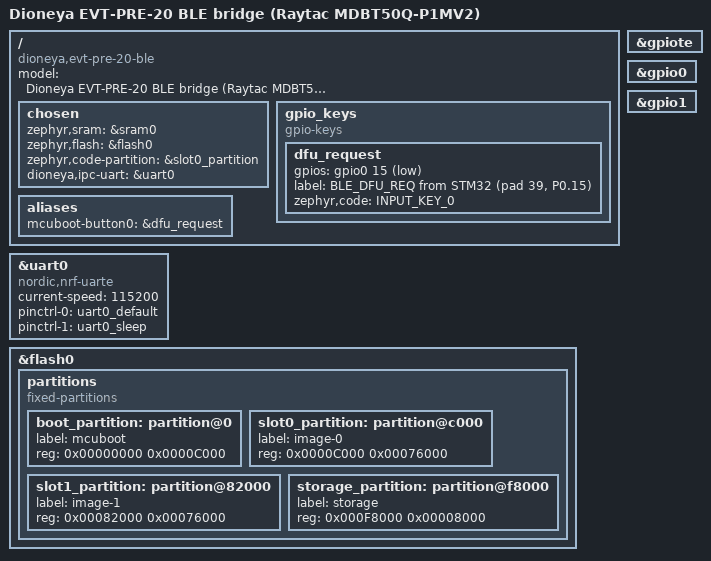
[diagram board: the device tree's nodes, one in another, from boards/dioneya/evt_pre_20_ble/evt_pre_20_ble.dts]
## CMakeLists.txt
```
# Dioneya nRF52840 BLE bridge — Zephyr / nRF Connect SDK application.
# NOT built by the repository CI (no NCS there): build with west on a machine with NCS v2.7+:
#   west build -b evt_pre_20_ble          firmware/targets/nrf52840_ble   # Rev.A carrier, U11 Raytac MDBT50Q-P1MV2
#   west build -b nrf52840dk/nrf52840     firmware/targets/nrf52840_ble   # bench on the DK (uart1 P1.01/P1.02 overlay)
# The bridge logic itself (zs_ble_bridge, zs_ipc_link, zs_ble_framing) is host-tested in firmware/tests.
cmake_minimum_required(VERSION 3.20.0)
list(APPEND BOARD_ROOT ${CMAKE_CURRENT_SOURCE_DIR})   # boards/dioneya/evt_pre_20_ble
find_package(Zephyr REQUIRED HINTS $ENV{ZEPHYR_BASE})
project(dioneya_nrf52840_ble)

set(ZS_FW_ROOT ${CMAKE_CURRENT_SOURCE_DIR}/../..)
target_sources(app PRIVATE
  src/main.c
  src/gatt.c
  src/ipc_uart.c
  ${ZS_FW_ROOT}/src/zs_ble_framing.c
  ${ZS_FW_ROOT}/src/zs_ipc_link.c
  ${ZS_FW_ROOT}/src/zs_ble_bridge.c
  ${ZS_FW_ROOT}/src/zs_sha256.c
)
target_include_directories(app PRIVATE ${ZS_FW_ROOT}/include src)
```

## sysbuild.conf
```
# NCS sysbuild: MCUboot in front of the bridge application (flash map: boards/dioneya/evt_pre_20_ble + pm_static.yml).
# The signing key is the pilot key from the PKI: muhoed-pki nrf-boot-key  ->  <pki>/nrf-boot/nrf-boot.key.pem
#   west build -b evt_pre_20_ble firmware/targets/nrf52840_ble -- -DSB_CONFIG_BOOT_SIGNATURE_KEY_FILE=\"/abs/path/nrf-boot.key.pem\"
SB_CONFIG_BOOTLOADER_MCUBOOT=y
SB_CONFIG_BOOT_SIGNATURE_TYPE_ECDSA_P256=y
# NCS 2.7 / MCUboot uses the move-based, no-scratch swap under this
# Kconfig name.  The two 472 KiB slots in pm_static.yml are equal-sized.
SB_CONFIG_MCUBOOT_MODE_SWAP_WITHOUT_SCRATCH=y
```

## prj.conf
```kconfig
# Dioneya nRF52840 BLE bridge (ICD addendum B + C)
CONFIG_BT=y
CONFIG_BT_PERIPHERAL=y
CONFIG_BT_CTLR=y
CONFIG_BT_DEVICE_NAME="DIO-EVT-000"
CONFIG_BT_DEVICE_NAME_DYNAMIC=y
CONFIG_BT_DEVICE_NAME_MAX=31
CONFIG_BT_MAX_CONN=1
CONFIG_BT_SMP=y
CONFIG_BT_SMP_SC_PAIR_ONLY=y
CONFIG_BT_FIXED_PASSKEY=y
CONFIG_BT_BONDABLE=n
CONFIG_BT_GATT_DYNAMIC_DB=n
CONFIG_BT_GATT_CLIENT=n
# ATT MTU 247 (addendum B.2): ACL 251-byte buffers on both directions
CONFIG_BT_L2CAP_TX_MTU=247
CONFIG_BT_BUF_ACL_RX_SIZE=251
CONFIG_BT_BUF_ACL_TX_SIZE=251
CONFIG_BT_DATA_LEN_UPDATE=y
CONFIG_BT_CTLR_DATA_LENGTH_MAX=251
# The installer (GATT client) initiates ATT MTU exchange.  A peripheral-only
# bridge must not enable BT_GATT_AUTO_UPDATE_MTU, which depends on GATT client.
# Application diagnostics use RTT and never consume the STM32 IPC UART.
CONFIG_USE_SEGGER_RTT=y
CONFIG_RTT_CONSOLE=y
CONFIG_CONSOLE=y
# UART link to the STM32U585 (uart1, interrupt driven)
CONFIG_SERIAL=y
CONFIG_UART_INTERRUPT_DRIVEN=y
CONFIG_RING_BUFFER=y
CONFIG_MAIN_STACK_SIZE=4096
CONFIG_SYSTEM_WORKQUEUE_STACK_SIZE=4096
CONFIG_LOG=y
CONFIG_LOG_DEFAULT_LEVEL=3
CONFIG_ASSERT=y
# MCUboot image management: the bridge confirms itself once the STM32 link is proven (addendum C.6).
CONFIG_FLASH=y
CONFIG_FLASH_MAP=y
CONFIG_STREAM_FLASH=y
CONFIG_IMG_MANAGER=y
CONFIG_MCUBOOT_IMG_MANAGER=y
CONFIG_MCUBOOT_IMGTOOL_SIGN_VERSION="0.1.0+2026101601"
```

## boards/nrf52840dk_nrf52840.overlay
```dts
/* Bring-up on the nRF52840 DK: uart1 on P1.01 (TX) / P1.02 (RX) toward the STM32U585 USART3 (PB10 TX / PB11 RX).
   The Rev.A station carrier assigns the module pins in the board contract; add an overlay per board there. */
&pinctrl {
	uart1_default: uart1_default {
		group1 { psels = <NRF_PSEL(UART_TX, 1, 1)>; };
		group2 { psels = <NRF_PSEL(UART_RX, 1, 2)>; bias-pull-up; };
	};
	uart1_sleep: uart1_sleep {
		group1 { psels = <NRF_PSEL(UART_TX, 1, 1)>, <NRF_PSEL(UART_RX, 1, 2)>; low-power-enable; };
	};
};

&uart1 {
	status = "okay";
	current-speed = <115200>;
	pinctrl-0 = <&uart1_default>;
	pinctrl-1 = <&uart1_sleep>;
	pinctrl-names = "default", "sleep";
};

/ {
	chosen {
		dioneya,ipc-uart = &uart1;
	};
};
```

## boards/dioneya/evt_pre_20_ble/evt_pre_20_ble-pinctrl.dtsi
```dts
/* U11 pad 22 P0.06 = UARTE TX (BLE_RX net), pad 24 P0.08 = UARTE RX (BLE_TX net); no RTS/CTS on Rev.A. */
&pinctrl {
	uart0_default: uart0_default {
		group1 {
			psels = <NRF_PSEL(UART_TX, 0, 6)>;
		};
		group2 {
			psels = <NRF_PSEL(UART_RX, 0, 8)>;
			bias-pull-up;
		};
	};

	uart0_sleep: uart0_sleep {
		group1 {
			psels = <NRF_PSEL(UART_TX, 0, 6)>,
				<NRF_PSEL(UART_RX, 0, 8)>;
			low-power-enable;
		};
	};
};
```

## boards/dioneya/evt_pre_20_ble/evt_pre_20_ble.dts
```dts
/*
 * Dioneya EVT-PRE-20 Rev.A, BLE bridge: Raytac MDBT50Q-P1MV2 (nRF52840 QIAA) = U11 on PCB-MAIN.
 * Wiring from hardware/PCB_MAIN_BLE_PIN_AUTHORITY_REV_A.csv (authority: Raytac Ver.L + Rev.A netlist):
 *   pad 22 P0.06  nRF UARTE TX  -> STM32 PB11 USART3_RX   (net BLE_RX, 22 R series at U11)
 *   pad 24 P0.08  nRF UARTE RX  <- STM32 PB10 USART3_TX   (net BLE_TX, 22 R series at STM32)
 *   pad 39 P0.15  BLE_DFU_REQ   <- STM32 PB2 open-drain, 10 k pull-up, active LOW, sampled by the bootloader at reset release
 *   pad 40 P0.18/nRESET         <- reset buffer from STM32 BLE_EN (LOW = held in reset), 10 k pull-up
 *   VDD = VDDH = 3V3_DIGITAL (normal-voltage mode, Reg0 DC/DC unused), no 32.768 kHz crystal, no NFC, no USB, no flow control.
 *   SWDIO/SWDCLK -> TP_BLE_SWD fixture pads (separate from the STM32 SWD).
 */
/dts-v1/;
#include <nordic/nrf52840_qiaa.dtsi>
#include <zephyr/dt-bindings/input/input-event-codes.h>
#include "evt_pre_20_ble-pinctrl.dtsi"

/ {
	model = "Dioneya EVT-PRE-20 BLE bridge (Raytac MDBT50Q-P1MV2)";
	compatible = "dioneya,evt-pre-20-ble";

	chosen {
		zephyr,sram = &sram0;
		zephyr,flash = &flash0;
		zephyr,code-partition = &slot0_partition;
		dioneya,ipc-uart = &uart0;
	};

	gpio_keys {
		compatible = "gpio-keys";
		dfu_request: dfu_request {
			gpios = <&gpio0 15 GPIO_ACTIVE_LOW>;
			label = "BLE_DFU_REQ from STM32 (pad 39, P0.15)";
			zephyr,code = <INPUT_KEY_0>;
		};
	};

	aliases {
		mcuboot-button0 = &dfu_request;
	};
};

&gpiote {
	status = "okay";
};

&gpio0 {
	status = "okay";
};

&gpio1 {
	status = "okay";
};

&uart0 {
	compatible = "nordic,nrf-uarte";
	status = "okay";
	current-speed = <115200>;
	pinctrl-0 = <&uart0_default>;
	pinctrl-1 = <&uart0_sleep>;
	pinctrl-names = "default", "sleep";
};

&flash0 {
	partitions {
		compatible = "fixed-partitions";
		#address-cells = <1>;
		#size-cells = <1>;

		boot_partition: partition@0 {
			label = "mcuboot";
			reg = <0x00000000 0x0000C000>;
		};
		slot0_partition: partition@c000 {
			label = "image-0";
			reg = <0x0000C000 0x00076000>;
		};
		slot1_partition: partition@82000 {
			label = "image-1";
			reg = <0x00082000 0x00076000>;
		};
		storage_partition: partition@f8000 {
			label = "storage";
			reg = <0x000F8000 0x00008000>;
		};
	};
};
```

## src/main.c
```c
/*
 * Dioneya nRF52840 BLE bridge: advertising, connection/security events, pairing passkey derived
 * from the label secret, and the glue between zs_ble_bridge and the Zephyr stack.
 * Pairing (addendum B.7): LE Secure Connections, passkey entry with a fixed 6-digit passkey
 *   passkey = BE32(SHA-256("DIO-PAIR-V1" || secret)[0..3]) mod 1_000_000
 * The phone derives the same number from the scanned label and shows it to the installer.
 */
#include "bridge_app.h"

#include <zephyr/bluetooth/bluetooth.h>
#include <zephyr/bluetooth/conn.h>
#include <zephyr/bluetooth/gap.h>
#include <zephyr/bluetooth/uuid.h>
#include <zephyr/kernel.h>
#include <zephyr/logging/log.h>
#include <string.h>
#ifdef CONFIG_MCUBOOT_IMG_MANAGER
#include <zephyr/dfu/mcuboot.h>
#endif

LOG_MODULE_REGISTER(dio_bridge, LOG_LEVEL_INF);

zs_ble_bridge_t bridge;
static bool window_open;
static struct k_work_delayable window_timer;
static char local_name[32] = CONFIG_BT_DEVICE_NAME;

static const struct bt_data adv_data[] = {
  BT_DATA_BYTES(BT_DATA_FLAGS, BT_LE_AD_GENERAL | BT_LE_AD_NO_BREDR),
  BT_DATA_BYTES(BT_DATA_UUID128_ALL, BT_UUID_128_ENCODE(0xd10e0100u, 0x5a53, 0x4c55, 0xb0a1, 0x000000000000ULL)),
};
static struct bt_data scan_rsp[1];

static void start_advertising(void) {
  scan_rsp[0] = (struct bt_data)BT_DATA(BT_DATA_NAME_COMPLETE, local_name, strlen(local_name));
  const int err = bt_le_adv_start(BT_LE_ADV_CONN, adv_data, ARRAY_SIZE(adv_data), scan_rsp, ARRAY_SIZE(scan_rsp));
  if (err && err != -EALREADY) LOG_ERR("adv start %d", err);
}

static void window_expired(struct k_work *work) {
  ARG_UNUSED(work);
  window_open = false;
  (void)bt_le_adv_stop();
  LOG_INF("service window closed");
}

void app_advertise(bool on, uint16_t seconds) {
  window_open = on;
  if (on) {
    start_advertising();
    if (seconds) k_work_reschedule(&window_timer, K_SECONDS(seconds)); else k_work_cancel_delayable(&window_timer);
  } else {
    k_work_cancel_delayable(&window_timer);
    (void)bt_le_adv_stop();
  }
}

/* A freshly swapped-in image is confirmed only after the STM32 has talked to it (IDENTITY_SET arrives at the
   service init and after every recovery); an image that never hears the STM32 is reverted by MCUboot on the
   next reset, which is how a broken bridge update heals itself (addendum C.6). */
static void confirm_running_image(void) {
#ifdef CONFIG_MCUBOOT_IMG_MANAGER
  if (!boot_is_img_confirmed()) {
    const int err = boot_write_img_confirmed();
    LOG_INF("image confirmed (%d)", err);
  }
#endif
}

void app_set_local_name(const char *name) {
  strncpy(local_name, name, sizeof(local_name) - 1u);
  local_name[sizeof(local_name) - 1u] = '\0';
  (void)bt_set_name(local_name);
  confirm_running_image();
}

void app_set_pairing_secret(const uint8_t secret[16]) {
  (void)bt_passkey_set(zs_ble_pairing_passkey(secret));   /* B.7, host-tested in firmware/tests/test_ble_bridge.c */
  LOG_INF("pairing passkey installed");
}

/* ---- connection and security ------------------------------------------------------------ */

static void connected(struct bt_conn *conn, uint8_t err) {
  if (err) { LOG_WRN("connect failed %u", err); return; }
  gatt_set_conn(bt_conn_ref(conn));
  zs_ble_bridge_on_link(&bridge, 1u);
  LOG_INF("connected");
}

static void disconnected(struct bt_conn *conn, uint8_t reason) {
  LOG_INF("disconnected %u", reason);
  gatt_set_conn(NULL);
  bt_conn_unref(conn);
  zs_ble_bridge_on_link(&bridge, 0u);
  if (window_open) start_advertising();
}

static void security_changed(struct bt_conn *conn, bt_security_t level, enum bt_security_err err) {
  ARG_UNUSED(conn);
  if (err == BT_SECURITY_ERR_SUCCESS && level >= BT_SECURITY_L3) zs_ble_bridge_on_link(&bridge, 2u);   /* authenticated (MITM) LESC */
  LOG_INF("security level %d err %d", level, err);
}

BT_CONN_CB_DEFINE(conn_cb) = {
  .connected = connected,
  .disconnected = disconnected,
  .security_changed = security_changed,
};

static void auth_cancel(struct bt_conn *conn) { ARG_UNUSED(conn); LOG_WRN("pairing cancelled"); }
static void auth_passkey_display(struct bt_conn *conn, unsigned int passkey) { ARG_UNUSED(conn); ARG_UNUSED(passkey); }
static const struct bt_conn_auth_cb auth_cb = {
  .passkey_display = auth_passkey_display,   /* display capability: the phone enters the label-derived passkey */
  .cancel = auth_cancel,
};

/* ---- bridge port ------------------------------------------------------------------------- */

static bool port_uart_send(void *ctx, const uint8_t *wire, size_t len) { ARG_UNUSED(ctx); return ipc_uart_send(wire, len); }
static bool port_notify(void *ctx, uint16_t id, const uint8_t *frame, size_t len) { ARG_UNUSED(ctx); return gatt_notify_frame(id, frame, len); }
static size_t port_att(void *ctx) { ARG_UNUSED(ctx); return gatt_att_payload(); }
static void port_advertise(void *ctx, bool on, uint16_t s) { ARG_UNUSED(ctx); app_advertise(on, s); }
static void port_name(void *ctx, const char *n) { ARG_UNUSED(ctx); app_set_local_name(n); }
static void port_secret(void *ctx, const uint8_t s[16]) { ARG_UNUSED(ctx); app_set_pairing_secret(s); }

static const zs_ble_bridge_port_t port = {NULL, port_uart_send, port_notify, port_att, port_advertise, port_name, port_secret};

int main(void) {
  k_work_init_delayable(&window_timer, window_expired);
  zs_ble_bridge_init(&bridge, &port);
  if (ipc_uart_init()) return -1;
  int err = bt_enable(NULL);
  if (err) { LOG_ERR("bt_enable %d", err); return err; }
  (void)bt_conn_auth_cb_register(&auth_cb);
  (void)gatt_init();
  LOG_INF("Dioneya BLE bridge ready; waiting for the STM32 (IDENTITY_SET / SERVICE_WINDOW)");
  for (;;) ipc_uart_poll();   /* feeds the bridge; every reply goes back over the UART from the same thread */
  return 0;
}
```

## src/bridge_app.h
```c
#ifndef BRIDGE_APP_H
#define BRIDGE_APP_H
/* Glue between the portable zs_ble_bridge core and the Zephyr BLE stack / UART. */
#include "zs_ble_bridge.h"
#include <zephyr/bluetooth/conn.h>

extern zs_ble_bridge_t bridge;

/* gatt.c */
int gatt_init(void);
bool gatt_notify_frame(uint16_t char_id, const uint8_t *frame, size_t len);
size_t gatt_att_payload(void);
void gatt_set_conn(struct bt_conn *conn);

/* ipc_uart.c */
int ipc_uart_init(void);
bool ipc_uart_send(const uint8_t *wire, size_t len);
/* Drains received bytes into the bridge; called from the main loop. */
void ipc_uart_poll(void);

/* main.c */
void app_advertise(bool on, uint16_t seconds);
void app_set_local_name(const char *name);
void app_set_pairing_secret(const uint8_t secret[16]);

#endif
```

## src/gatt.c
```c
/* GATT table of ICD addendum B.1 on top of the portable bridge (zs_ble_bridge). */
#include "bridge_app.h"

#include <zephyr/bluetooth/bluetooth.h>
#include <zephyr/bluetooth/gatt.h>
#include <zephyr/bluetooth/uuid.h>
#include <zephyr/logging/log.h>

LOG_MODULE_REGISTER(gatt, LOG_LEVEL_INF);

/* d10eXXXX-5a53-4c55-b0a1-000000000000 */
#define DIO_UUID(id16) BT_UUID_DECLARE_128(BT_UUID_128_ENCODE(0xd10e0000u | (id16), 0x5a53, 0x4c55, 0xb0a1, 0x000000000000ULL))

static struct bt_conn *current_conn;

static ssize_t read_cb(struct bt_conn *conn, const struct bt_gatt_attr *attr, void *buf, uint16_t len, uint16_t offset) {
  const uint16_t char_id = (uint16_t)(uintptr_t)attr->user_data;
  uint8_t frame[ZS_BLE_ATT_PAYLOAD_MAX];
  size_t n;
  if (offset != 0u) return BT_GATT_ERR(BT_ATT_ERR_INVALID_OFFSET); /* every ATT read is one frame (B.2) */
  if (!zs_ble_bridge_on_gatt_read(&bridge, char_id, frame, sizeof(frame), &n)) return BT_GATT_ERR(BT_ATT_ERR_UNLIKELY);
  return bt_gatt_attr_read(conn, attr, buf, len, 0u, frame, (uint16_t)n);
}

static ssize_t write_cb(struct bt_conn *conn, const struct bt_gatt_attr *attr, const void *buf, uint16_t len, uint16_t offset, uint8_t flags) {
  const uint16_t char_id = (uint16_t)(uintptr_t)attr->user_data;
  ARG_UNUSED(conn); ARG_UNUSED(flags);
  if (offset != 0u) return BT_GATT_ERR(BT_ATT_ERR_INVALID_OFFSET);
  if (!zs_ble_bridge_on_gatt_write(&bridge, char_id, buf, len)) return BT_GATT_ERR(BT_ATT_ERR_VALUE_NOT_ALLOWED);
  return len;
}

static void ccc_changed(const struct bt_gatt_attr *attr, uint16_t value) { ARG_UNUSED(attr); ARG_UNUSED(value); }

#define CHAR_ID(id) ((void *)(uintptr_t)(id))
/* Reads before pairing are allowed only for identity (B.4); everything else needs an authenticated (MITM) link. */
BT_GATT_SERVICE_DEFINE(dio_device_info,
  BT_GATT_PRIMARY_SERVICE(DIO_UUID(0x0100)),
  BT_GATT_CHARACTERISTIC(DIO_UUID(0x0101), BT_GATT_CHRC_READ, BT_GATT_PERM_READ, read_cb, NULL, CHAR_ID(ZS_CHAR_IDENTITY)),
);

BT_GATT_SERVICE_DEFINE(dio_configuration,
  BT_GATT_PRIMARY_SERVICE(DIO_UUID(0x0200)),
  BT_GATT_CHARACTERISTIC(DIO_UUID(0x0201), BT_GATT_CHRC_READ | BT_GATT_CHRC_NOTIFY, BT_GATT_PERM_READ_AUTHEN, read_cb, NULL, CHAR_ID(ZS_CHAR_CONFIG_READ)),
  BT_GATT_CCC(ccc_changed, BT_GATT_PERM_READ | BT_GATT_PERM_WRITE_AUTHEN),
  BT_GATT_CHARACTERISTIC(DIO_UUID(0x0202), BT_GATT_CHRC_WRITE | BT_GATT_CHRC_NOTIFY, BT_GATT_PERM_WRITE_AUTHEN, NULL, write_cb, CHAR_ID(ZS_CHAR_CONFIG_WRITE)),
  BT_GATT_CCC(ccc_changed, BT_GATT_PERM_READ | BT_GATT_PERM_WRITE_AUTHEN),
  BT_GATT_CHARACTERISTIC(DIO_UUID(0x0203), BT_GATT_CHRC_READ | BT_GATT_CHRC_WRITE | BT_GATT_CHRC_NOTIFY, BT_GATT_PERM_READ_AUTHEN | BT_GATT_PERM_WRITE_AUTHEN, read_cb, write_cb, CHAR_ID(ZS_CHAR_INSTALLATION_POSITION)),
  BT_GATT_CCC(ccc_changed, BT_GATT_PERM_READ | BT_GATT_PERM_WRITE_AUTHEN),
  BT_GATT_CHARACTERISTIC(DIO_UUID(0x0204), BT_GATT_CHRC_READ | BT_GATT_CHRC_WRITE | BT_GATT_CHRC_NOTIFY, BT_GATT_PERM_READ_AUTHEN | BT_GATT_PERM_WRITE_AUTHEN, read_cb, write_cb, CHAR_ID(ZS_CHAR_POSITION_TRUST_POLICY)),
  BT_GATT_CCC(ccc_changed, BT_GATT_PERM_READ | BT_GATT_PERM_WRITE_AUTHEN),
  BT_GATT_CHARACTERISTIC(DIO_UUID(0x0205), BT_GATT_CHRC_READ | BT_GATT_CHRC_WRITE | BT_GATT_CHRC_NOTIFY, BT_GATT_PERM_READ_AUTHEN | BT_GATT_PERM_WRITE_AUTHEN, read_cb, write_cb, CHAR_ID(ZS_CHAR_SESSION_ROLE)),   /* B.9 */
  BT_GATT_CCC(ccc_changed, BT_GATT_PERM_READ | BT_GATT_PERM_WRITE_AUTHEN),
  BT_GATT_CHARACTERISTIC(DIO_UUID(0x0206), BT_GATT_CHRC_READ | BT_GATT_CHRC_WRITE | BT_GATT_CHRC_NOTIFY, BT_GATT_PERM_READ_AUTHEN | BT_GATT_PERM_WRITE_AUTHEN, read_cb, write_cb, CHAR_ID(ZS_CHAR_STATION_SECRETS)),   /* v0.3 */
  BT_GATT_CCC(ccc_changed, BT_GATT_PERM_READ | BT_GATT_PERM_WRITE_AUTHEN),
);

BT_GATT_SERVICE_DEFINE(dio_diagnostics,
  BT_GATT_PRIMARY_SERVICE(DIO_UUID(0x0300)),
  BT_GATT_CHARACTERISTIC(DIO_UUID(0x0301), BT_GATT_CHRC_READ | BT_GATT_CHRC_NOTIFY, BT_GATT_PERM_READ_AUTHEN, read_cb, NULL, CHAR_ID(ZS_CHAR_STATUS)),
  BT_GATT_CCC(ccc_changed, BT_GATT_PERM_READ | BT_GATT_PERM_WRITE_AUTHEN),
  BT_GATT_CHARACTERISTIC(DIO_UUID(0x0302), BT_GATT_CHRC_READ | BT_GATT_CHRC_NOTIFY, BT_GATT_PERM_READ_AUTHEN, read_cb, NULL, CHAR_ID(ZS_CHAR_GNSS_INTEGRITY)),
  BT_GATT_CCC(ccc_changed, BT_GATT_PERM_READ | BT_GATT_PERM_WRITE_AUTHEN),
  BT_GATT_CHARACTERISTIC(DIO_UUID(0x0303), BT_GATT_CHRC_WRITE | BT_GATT_CHRC_NOTIFY, BT_GATT_PERM_WRITE_AUTHEN, NULL, write_cb, CHAR_ID(ZS_CHAR_SELF_TEST)),
  BT_GATT_CCC(ccc_changed, BT_GATT_PERM_READ | BT_GATT_PERM_WRITE_AUTHEN),
);

/* Finds the characteristic value attribute for a bridge char id (static tables, so a linear scan is fine). */
static const struct bt_gatt_attr *value_attr(uint16_t char_id) {
  const struct bt_gatt_service_static *svcs[] = {&dio_device_info, &dio_configuration, &dio_diagnostics};
  for (size_t s = 0u; s < ARRAY_SIZE(svcs); s++)
    for (size_t i = 0u; i < svcs[s]->attr_count; i++) {
      const struct bt_gatt_attr *a = &svcs[s]->attrs[i];
      if (a->user_data == CHAR_ID(char_id) && (a->read == read_cb || a->write == write_cb)) return a;
    }
  return NULL;
}

bool gatt_notify_frame(uint16_t char_id, const uint8_t *frame, size_t len) {
  const struct bt_gatt_attr *attr = value_attr(char_id);
  if (attr == NULL || current_conn == NULL) return false;
  if (!bt_gatt_is_subscribed(current_conn, attr, BT_GATT_CCC_NOTIFY)) return false;
  return bt_gatt_notify(current_conn, attr, frame, (uint16_t)len) == 0;
}

size_t gatt_att_payload(void) {
  if (current_conn == NULL) return ZS_BLE_ATT_PAYLOAD_MIN;
  const uint16_t mtu = bt_gatt_get_mtu(current_conn);
  if (mtu < ZS_BLE_ATT_PAYLOAD_MIN + 3u) return ZS_BLE_ATT_PAYLOAD_MIN;
  return mtu - 3u > ZS_BLE_ATT_PAYLOAD_MAX ? ZS_BLE_ATT_PAYLOAD_MAX : mtu - 3u;
}

void gatt_set_conn(struct bt_conn *conn) { current_conn = conn; }

int gatt_init(void) { return 0; }
```

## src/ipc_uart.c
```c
/* Interrupt-driven UART to the STM32U585: RX bytes go to a ring buffer, the main loop feeds the bridge. */
#include "bridge_app.h"

#include <zephyr/device.h>
#include <zephyr/drivers/uart.h>
#include <zephyr/kernel.h>
#include <zephyr/logging/log.h>
#include <zephyr/sys/ring_buffer.h>

LOG_MODULE_REGISTER(ipc_uart, LOG_LEVEL_INF);

static const struct device *const uart_dev = DEVICE_DT_GET(DT_CHOSEN(dioneya_ipc_uart));
RING_BUF_DECLARE(rx_ring, 2048);
static struct k_sem rx_sem;

static void uart_isr(const struct device *dev, void *user_data) {
  uint8_t buf[64];
  ARG_UNUSED(user_data);
  while (uart_irq_update(dev) && uart_irq_is_pending(dev)) {
    if (!uart_irq_rx_ready(dev)) break;
    const int n = uart_fifo_read(dev, buf, sizeof(buf));
    if (n <= 0) break;
    if (ring_buf_put(&rx_ring, buf, (uint32_t)n) != (uint32_t)n) LOG_WRN("rx ring overflow");
    k_sem_give(&rx_sem);
  }
}

int ipc_uart_init(void) {
  if (!device_is_ready(uart_dev)) { LOG_ERR("ipc uart not ready"); return -ENODEV; }
  k_sem_init(&rx_sem, 0, 1);
  uart_irq_callback_user_data_set(uart_dev, uart_isr, NULL);
  uart_irq_rx_enable(uart_dev);
  return 0;
}

bool ipc_uart_send(const uint8_t *wire, size_t len) {
  for (size_t i = 0u; i < len; i++) uart_poll_out(uart_dev, wire[i]);
  return true;
}

void ipc_uart_poll(void) {
  uint8_t buf[64];
  (void)k_sem_take(&rx_sem, K_MSEC(100));
  for (;;) {
    const uint32_t n = ring_buf_get(&rx_ring, buf, sizeof(buf));
    if (n == 0u) break;
    zs_ble_bridge_on_uart_rx(&bridge, buf, n);
  }
}
```
